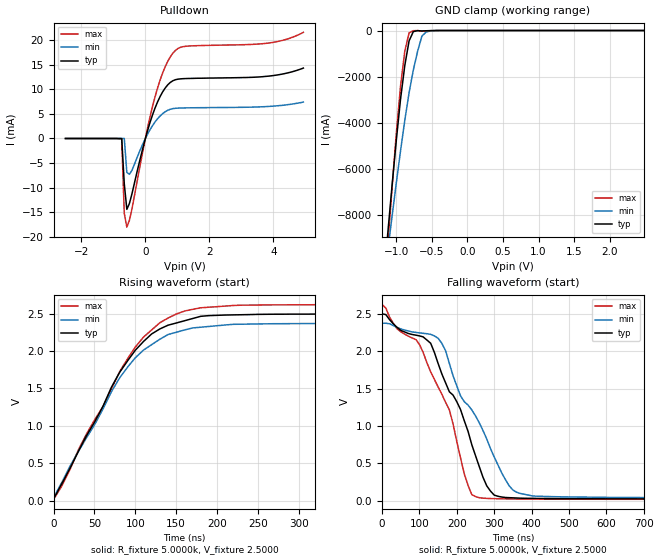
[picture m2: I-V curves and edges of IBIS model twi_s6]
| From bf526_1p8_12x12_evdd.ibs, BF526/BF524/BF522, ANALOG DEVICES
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[Model]   twi_s6
Model_type I/O_open_drain
Polarity   Non-Inverting
Enable   Active-Low
Vinl =   0.7500V
Vinh =   1.7500V
Vmeas =  1.2500V
Cref =   50.0000pF
Rref =   5.0000k
Vref =   2.5000V
C_comp   7.1300pF   6.4200pF   7.8500pF
[Temperature Range]   25.0000   0.1250k   0.0
[Voltage Range]   2.5000V   2.3750V   2.6250V
[Pullup Reference]   2.5000V   2.3750V   2.6250V
[Pulldown Reference]   0.0V   0.0V   0.0V
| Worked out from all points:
|   slope of the pulldown table from 0 to 0.375 V, typ, clamps not added: 50.9 ohm
|   GND clamp passes 1 mA (typ) near -0.43 V on its own axis
|   rising waveform, R_fixture 5.0000k, V_fixture 2.5000: 20-80 % time 75.4ns typ, 77.3ns min, 78.7ns max; typ from 0.021 V to 2.5 V
|   falling waveform, R_fixture 5.0000k, V_fixture 2.5000: 20-80 % time 117ns typ, 132ns min, 113ns max; typ from 2.5 V to 0.021 V
[Pulldown]
|Voltage   I(typ)   I(min)   I(max)
-2.5V     0A         0A         0A
-740mV    -20uA      0A         -54uA
-660mV    -9.21mA    0A         -15.24mA
-580mV    -14.43mA   -6.9mA     -18.05mA
-420mV    -11.27mA   -6.485mA   -14.35mA
-20mV     -489.5uA   -271.8uA   -650.4uA
300mV     6.168mA    3.352mA    8.441mA
620mV     10.28mA    5.448mA    14.63mA
860mV     11.76mA    6.085mA    17.38mA
1.26V     12.2mA     6.231mA    18.77mA
3.98V     12.8mA     6.579mA    19.56mA
4.94V     14.34mA    7.417mA    21.62mA
[GND_clamp]
|Voltage   I(typ)   I(min)   I(max)
-2.5V     -59.97A    -45.67A    -72.09A
-1.12V    -8.799A    -9.55A     -9.344A
-1.06V    -6.738A    -8.066A    -6.84A
-1V       -4.765A    -6.614A    -4.473A
-940mV    -2.967A    -5.209A    -2.401A
-880mV    -1.51A     -3.883A    -890.2mA
-820mV    -448.1mA   -2.694A    -100.8mA
-760mV    -46.3mA    -1.705A    -8.654mA
-700mV    -4.927mA   -897.9mA   -1.463mA
-640mV    -19.29mA   -242.9mA   -27.34mA
-580mV    -10.88mA   -64.03mA   -16.8mA
2.48V     785pA      18.81nA    1.1nA
[Ramp]
| variable   typ   min   max
dV/dt_r  1.4870/75.6132n   1.4031/77.4408n   1.5647/78.9275n
dV/dt_f  1.4874/0.1174u   1.4024/0.1316u   1.5652/0.1136u
R_load = 5.0000k
[Rising Waveform]
R_fixture= 5.0000k
V_fixture= 2.5000
V_fixture_min= 2.3750
V_fixture_max= 2.6250
L_fixture= 0.0H
C_fixture= 0.0F
|time   V(typ)   V(min)   V(max)
0s        20.6mV     35.47mV    16.21mV
60.61ns   1.265V     1.228V     1.26V
70.71ns   1.515V     1.455V     1.494V
80.81ns   1.715V     1.642V     1.725V
100ns     2.012V     1.911V     2.054V
130ns     2.297V     2.159V     2.38V
160ns     2.406V     2.283V     2.536V
180ns     2.466V     2.32V      2.58V
250ns     2.492V     2.364V     2.617V
1us       2.499V     2.374V     2.624V
[Falling Waveform]
R_fixture= 5.0000k
V_fixture= 2.5000
V_fixture_min= 2.3750
V_fixture_max= 2.6250
L_fixture= 0.0H
C_fixture= 0.0F
|time   V(typ)   V(min)   V(max)
0s        2.5V       2.374V     2.625V
100ns     2.205V     2.245V     2.09V
130ns     2.106V     2.225V     1.724V
160ns     1.694V     2.104V     1.422V
180ns     1.456V     1.835V     1.214V
220ns     1.067V     1.323V     354.6mV
250ns     600.1mV    1.133V     53.11mV
300ns     72.67mV    582.5mV    25.56mV
370ns     31.89mV    94.62mV    20.48mV
1us       20.94mV    36.59mV    16.31mV
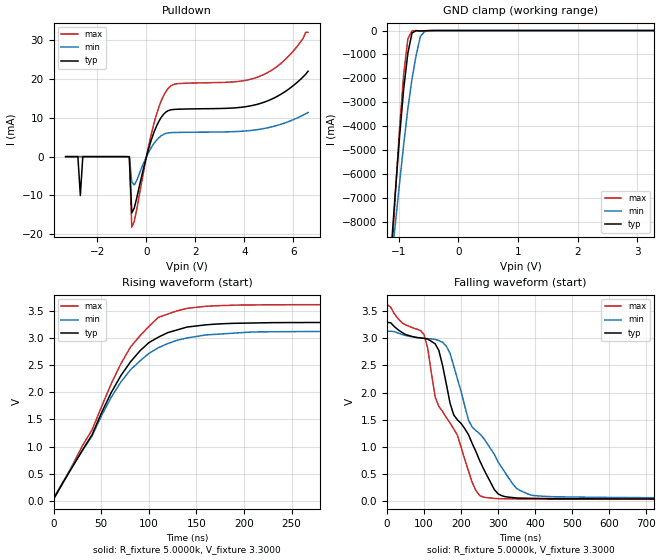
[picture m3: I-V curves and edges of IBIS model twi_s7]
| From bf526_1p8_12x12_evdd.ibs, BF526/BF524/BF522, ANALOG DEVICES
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[Model]   twi_s7
Model_type I/O_open_drain
Polarity   Non-Inverting
Enable   Active-Low
Vinl =   0.9900V
Vinh =   2.3100V
Vmeas =  1.6500V
Cref =   50.0000pF
Rref =   5.0000k
Vref =   3.3000V
C_comp   7.1300pF   6.4200pF   7.8500pF
[Temperature Range]   25.0000   0.1250k   0.0
[Voltage Range]   3.3000V   3.1350V   3.6300V
[Pullup Reference]   3.3000V   3.1350V   3.6300V
[Pulldown Reference]   0.0V   0.0V   0.0V
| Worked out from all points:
|   slope of the pulldown table from 0 to 0.495 V, typ, clamps not added: 55.2 ohm
|   GND clamp passes 1 mA (typ) near -0.44 V on its own axis
|   rising waveform, R_fixture 5.0000k, V_fixture 3.3000: 20-80 % time 62.7ns typ, 66ns min, 61.5ns max; typ from 0.027 V to 3.3 V
|   falling waveform, R_fixture 5.0000k, V_fixture 3.3000: 20-80 % time 109ns typ, 126ns min, 104ns max; typ from 3.3 V to 0.028 V
[Pulldown]
|Voltage   I(typ)   I(min)   I(max)
-3.3V     0A         0A         0A
-2.8V     0A         0A         0A
-2.7V     -10mA      0A         0A
-2.6V     0A         0A         0A
-700mV    -34uA      0A         -69uA
-600mV    -14.49mA   -6.5mA     -18.15mA
-500mV    -13.25mA   -7.29mA    -16.66mA
300mV     6.168mA    3.352mA    8.441mA
900mV     11.88mA    6.125mA    17.68mA
4.6V      13.61mA    7.021mA    20.62mA
5.6V      16.49mA    8.563mA    24.62mA
6.6V      22mA       11.38mA    32mA
[GND_clamp]
|Voltage   I(typ)   I(min)   I(max)
-3.3V     -90.22A    -67.03A    -109.2A
-1.13V    -9.148A    -9.799A    -9.77A
-1.06V    -6.738A    -8.066A    -6.84A
-990mV    -4.45A     -6.376A    -4.1A
-920mV    -2.435A    -4.756A    -1.824A
-850mV    -941.8mA   -3.266A    -348.1mA
-780mV    -99.67mA   -2.011A    -19.24mA
-710mV    -7.041mA   -1.022A    -1.727mA
-640mV    -19.29mA   -242.9mA   -27.34mA
-570mV    -9.687mA   -51.15mA   -15.19mA
-500mV    -3.403mA   -11.15mA   -6.097mA
3.28V     11.02nA    63.01nA    22.06nA
[Ramp]
| variable   typ   min   max
dV/dt_r  1.9630/62.0862n   1.8515/65.3191n   2.1633/60.9264n
dV/dt_f  1.9627/0.1093u   1.8507/0.1256u   2.1639/0.1044u
R_load = 5.0000k
[Rising Waveform]
R_fixture= 5.0000k
V_fixture= 3.3000
V_fixture_min= 3.1350
V_fixture_max= 3.6300
L_fixture= 0.0H
C_fixture= 0.0F
|time   V(typ)   V(min)   V(max)
0s        27.28mV    47.13mV    22.48mV
40.4ns    1.216V     1.194V     1.307V
60.61ns   1.999V     1.912V     2.163V
80.81ns   2.567V     2.42V      2.841V
100ns     2.921V     2.721V     3.221V
110ns     3.023V     2.827V     3.39V
140ns     3.21V      3.008V     3.556V
160ns     3.252V     3.065V     3.595V
240ns     3.293V     3.125V     3.623V
1us       3.299V     3.133V     3.628V
[Falling Waveform]
R_fixture= 5.0000k
V_fixture= 3.3000
V_fixture_min= 3.1350
V_fixture_max= 3.6300
L_fixture= 0.0H
C_fixture= 0.0F
|time   V(typ)   V(min)   V(max)
0s        3.299V     3.134V     3.629V
100ns     3.002V     3.003V     3.072V
130ns     2.901V     2.983V     1.917V
160ns     2.16V      2.857V     1.536V
180ns     1.586V     2.491V     1.324V
220ns     1.219V     1.486V     543.5mV
250ns     739.8mV    1.239V     92.98mV
300ns     122.8mV    714mV      34.68mV
390ns     40.78mV    97.82mV    27.47mV
1us       27.9mV     48.98mV    22.48mV
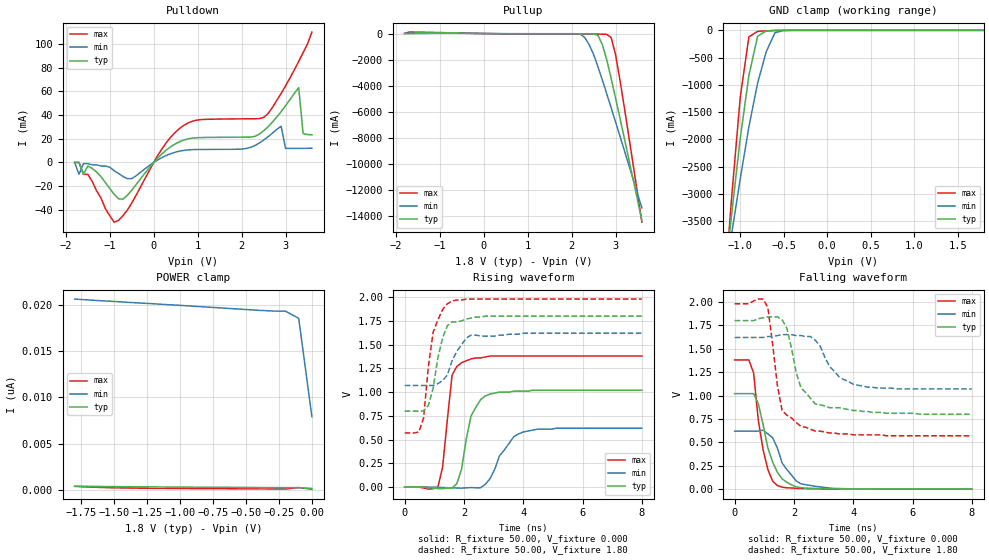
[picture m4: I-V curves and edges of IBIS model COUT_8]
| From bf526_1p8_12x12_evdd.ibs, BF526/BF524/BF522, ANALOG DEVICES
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|   Model prw0408swcdg_25
[Model]   COUT_8
Model_type   I/O
Polarity   Non-Inverting
Enable   Active-Low
Vinl =   0.70V
Vinh =   1.00V
Vmeas =   1.20V
Cref =  50.00pF
Rref =   1.00M
Vref =  0.000V
C_comp   4.81pF   4.33pF   5.29pF
[Temperature Range]   25.00   0.12k   -40.00
[Voltage Range]   1.80V   1.62V   1.98V
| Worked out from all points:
|   slope of the pulldown table from 0 to 0.27 V, typ, clamps not added: 27.1 ohm
|   slope of the pullup table from 0 to 0.27 V, typ, clamps not added: 26.9 ohm
|   GND clamp passes 1 mA (typ) near -0.53 V on its own axis
|   rising waveform, R_fixture 50.00, V_fixture 0.000: 20-80 % time 430ps typ, 666ps min, 273ps max; typ from 0 V to 1.02 V
|   rising waveform, R_fixture 50.00, V_fixture 1.80: 20-80 % time 392ps typ, 503ps min, 368ps max; typ from 0.8 V to 1.8 V
|   falling waveform, R_fixture 50.00, V_fixture 0.000: 20-80 % time 537ps typ, 626ps min, 387ps max; typ from 1.02 V to 0 V
|   falling waveform, R_fixture 50.00, V_fixture 1.80: 20-80 % time 633ps typ, 720ps min, 374ps max; typ from 1.8 V to 0.8 V
[Pulldown]
| voltage   I(typ)   I(min)   I(max)
-1.8V     0A         0A         0A
-1.7V     0A         -10mA      0A
-1.6V     -10mA      -1mA       -10mA
-1.4V     -5mA       -2mA       -16mA
-800mV    -30.7mA    -9.3mA     -48.85mA
500mV     15.88mA    8.74mA     25.76mA
2.5V      26.66mA    18.81mA    37.95mA
2.9V      42.91mA    30.55mA    58.28mA
3V        47.85mA    11.93mA    64.57mA
3.3V      63.16mA    11.88mA    85.3mA
3.4V      24.4mA     11.91mA    92.63mA
3.6V      23.31mA    12mA       110mA
[Pullup]
| voltage   I(typ)   I(min)   I(max)
-1.8V     1.48mA     550uA      10.03mA
-1.6V     2.84mA     560uA      110mA
2.2V      -22.71mA   -39.81mA   -37.75mA
2.3V      -23.18mA   -310mA     -37.82mA
2.4V      -25.42mA   -850mA     -37.94mA
2.6V      -130mA     -2.54A     -42.67mA
2.7V      -850mA     -3.56A     -49.75mA
2.8V      -2.01A     -4.61A     -61.08mA
2.9V      -3.43A     -5.68A     -310mA
3V        -4.93A     -6.76A     -1.61A
3.1V      -6.46A     -7.85A     -3.55A
3.6V      -14.31A    -13.35A    -14.44A
[GND_clamp]
| voltage   I(typ)   I(min)   I(max)
-1.8V     -14.28A    -11.35A    -18.41A
-1.2V     -4.9A      -4.81A     -5.19A
-1.1V     -3.4A      -3.75A     -3.1A
-1V       -1.99A     -2.73A     -1.24A
-900mV    -830mA     -1.77A     -120mA
-800mV    -110mA     -970mA     -19.21mA
-700mV    -9.89mA    -390mA     -9.78mA
-600mV    -2.57mA    -42.87mA   -3.5mA
-500mV    -460uA     -4.38mA    -550uA
1.8V      170pA      19.28nA    82.46pA
[POWER_clamp]
| voltage   I(typ)   I(min)   I(max)
-1.8V     420pA      20.63nA    400pA
-1.5V     370pA      20.37nA    240pA
-1.3V     350pA      20.2nA     200pA
-400mV    270pA      19.41nA    130pA
-200mV    260pA      19.32nA    110pA
-100mV    260pA      18.55nA    270pA
0V        170pA      7.92nA     95.65pA
[Ramp]
| variable   typ   min   max
dV/dt_r   0.61/0.48n   0.37/0.67n   0.83/0.28n
dV/dt_f   0.60/0.65n   0.33/0.73n   0.84/0.37n
R_load = 50.00
[Rising Waveform]
R_fixture = 50.00
V_fixture = 0.000
V_fixture_min = 0.000
V_fixture_max = 0.000
L_fixture = 0.000H
C_fixture = 0.000F
| time   V(typ)   V(min)   V(max)
0s        0V         0V         0V
1.12ns    -15.49mV   -2.64mV    -1.94mV
1.28ns    -16.64mV   -4.27mV    210mV
1.6ns     -11.55mV   -8.42mV    1.18V
1.92ns    190mV      -10.99mV   1.31V
2.24ns    750mV      -5.47mV    1.35V
2.72ns    960mV      29.12mV    1.37V
3.2ns     1V         330mV      1.38V
4ns       1.01V      580mV      1.38V
8ns       1.02V      620mV      1.38V
[Rising Waveform]
R_fixture = 50.00
V_fixture = 1.80
V_fixture_min = 1.62
V_fixture_max = 1.98
L_fixture = 0.000H
C_fixture = 0.000F
| time   V(typ)   V(min)   V(max)
0s        800mV      1.07V      570mV
480ps     800mV      1.07V      580mV
640ps     800mV      1.07V      730mV
800ps     860mV      1.07V      1.27V
960ps     1.04V      1.07V      1.63V
1.12ns    1.36V      1.09V      1.76V
1.28ns    1.57V      1.12V      1.87V
1.6ns     1.74V      1.33V      1.96V
2.24ns    1.78V      1.6V       1.98V
8ns       1.8V       1.62V      1.98V
[Falling Waveform]
R_fixture = 50.00
V_fixture = 0.000
V_fixture_min = 0.000
V_fixture_max = 0.000
L_fixture = 0.000H
C_fixture = 0.000F
| time   V(typ)   V(min)   V(max)
0s        1.02V      620mV      1.38V
480ps     1.02V      620mV      1.38V
640ps     1.02V      620mV      1.24V
800ps     910mV      620mV      730mV
960ps     690mV      630mV      420mV
1.12ns    440mV      590mV      210mV
1.44ns    180mV      440mV      38.63mV
1.6ns     110mV      280mV      21.04mV
2.24ns    15.2mV     56.58mV    6.95mV
8ns       40.15uV    66.62uV    5.02uV
[Falling Waveform]
R_fixture = 50.00
V_fixture = 1.80
V_fixture_min = 1.62
V_fixture_max = 1.98
L_fixture = 0.000H
C_fixture = 0.000F
| time   V(typ)   V(min)   V(max)
0s        1.8V       1.62V      1.98V
1.12ns    1.84V      1.63V      1.94V
1.44ns    1.84V      1.64V      1.11V
1.6ns     1.81V      1.65V      840mV
1.76ns    1.72V      1.65V      790mV
2.24ns    1.08V      1.64V      670mV
2.72ns    910mV      1.59V      620mV
3.2ns     870mV      1.31V      600mV
4ns       840mV      1.12V      580mV
8ns       800mV      1.07V      570mV
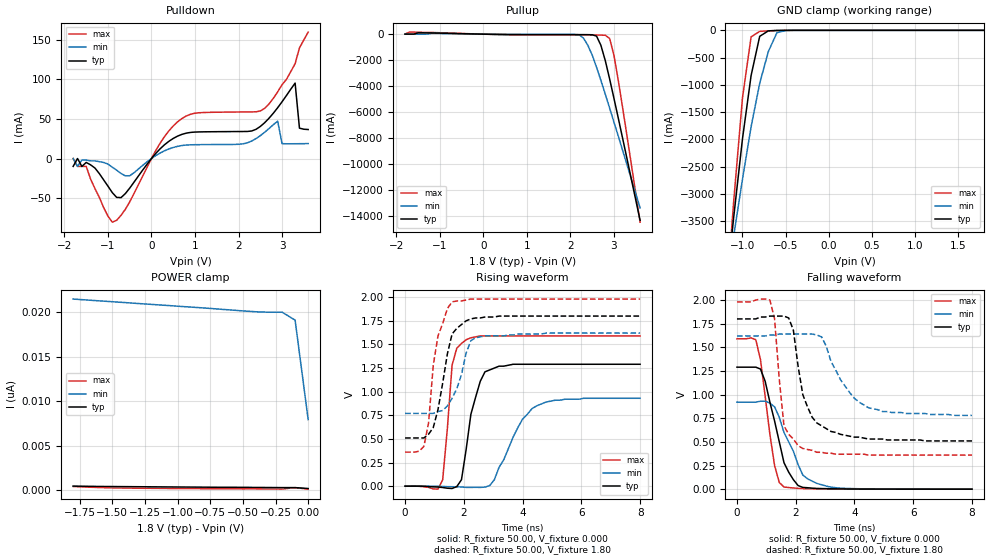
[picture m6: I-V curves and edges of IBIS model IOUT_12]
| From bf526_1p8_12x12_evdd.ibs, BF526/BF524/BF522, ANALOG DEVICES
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|   Model prw0812swcdg_25
[Model]   IOUT_12
Model_type   I/O
Polarity   Non-Inverting
Enable   Active-Low
Vinl =   0.70V
Vinh =   1.00V
Vmeas =   1.20V
Cref =  50.00pF
Rref =   1.00M
Vref =  0.000V
C_comp   4.56pF   4.10pF   5.01pF
[Temperature Range]   25.00   0.12k   -40.00
[Voltage Range]   1.80V   1.62V   1.98V
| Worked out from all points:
|   slope of the pulldown table from 0 to 0.27 V, typ, clamps not added: 17 ohm
|   slope of the pullup table from 0 to 0.27 V, typ, clamps not added: 16.9 ohm
|   GND clamp passes 1 mA (typ) near -0.53 V on its own axis
|   rising waveform, R_fixture 50.00, V_fixture 0.000: 20-80 % time 472ps typ, 926ps min, 244ps max; typ from 0 V to 1.29 V
|   rising waveform, R_fixture 50.00, V_fixture 1.80: 20-80 % time 464ps typ, 513ps min, 398ps max; typ from 0.51 V to 1.8 V
|   falling waveform, R_fixture 50.00, V_fixture 0.000: 20-80 % time 597ps typ, 726ps min, 407ps max; typ from 1.29 V to 0 V
|   falling waveform, R_fixture 50.00, V_fixture 1.80: 20-80 % time 570ps typ, 950ps min, 279ps max; typ from 1.8 V to 0.51 V
[Pulldown]
| voltage   I(typ)   I(min)   I(max)
-1.8V     -10mA      0A         0A
-1.4V     -8mA       -3mA       -26mA
-1V       -35mA      -7mA       -73mA
-800mV    -49.2mA    -14.8mA    -78.15mA
-500mV    -37.44mA   -21.82mA   -54.81mA
600mV     28.34mA    15.42mA    46.41mA
2.5V      40.54mA    28.91mA    60.13mA
2.9V      64.32mA    47.23mA    84.42mA
3V        71.8mA     18.76mA    93.51mA
3.3V      95.44mA    18.69mA    120mA
3.4V      38.41mA    18.74mA    140mA
3.6V      36.68mA    18.88mA    160mA
[Pullup]
| voltage   I(typ)   I(min)   I(max)
-1.8V     1.75mA     550uA      14.91mA
-1.6V     3.92mA     570uA      160mA
2.2V      -36.14mA   -47.43mA   -60.12mA
2.3V      -36.65mA   -310mA     -60.23mA
2.4V      -38.95mA   -860mA     -60.39mA
2.6V      -150mA     -2.55A     -65.28mA
2.7V      -860mA     -3.56A     -72.49mA
2.8V      -2.03A     -4.61A     -83.96mA
2.9V      -3.44A     -5.68A     -330mA
3V        -4.94A     -6.77A     -1.64A
3.1V      -6.47A     -7.85A     -3.57A
3.6V      -14.32A    -13.36A    -14.46A
[GND_clamp]
| voltage   I(typ)   I(min)   I(max)
-1.8V     -14.28A    -11.35A    -18.41A
-1.2V     -4.9A      -4.81A     -5.19A
-1.1V     -3.4A      -3.75A     -3.1A
-1V       -1.99A     -2.73A     -1.24A
-900mV    -830mA     -1.77A     -120mA
-800mV    -110mA     -970mA     -19.21mA
-700mV    -9.89mA    -390mA     -9.78mA
-600mV    -2.57mA    -42.87mA   -3.5mA
-500mV    -460uA     -4.38mA    -550uA
1.8V      170pA      19.94nA    82.46pA
[POWER_clamp]
| voltage   I(typ)   I(min)   I(max)
-1.8V     440pA      21.46nA    400pA
-1.3V     370pA      20.96nA    200pA
-400mV    290pA      20.03nA    130pA
-200mV    270pA      19.99nA    110pA
-100mV    270pA      19.09nA    270pA
0V        170pA      7.92nA     95.65pA
[Ramp]
| variable   typ   min   max
dV/dt_r   0.78/0.46n   0.56/0.89n   0.96/0.27n
dV/dt_f   0.77/0.58n   0.50/0.96n   0.97/0.31n
R_load = 50.00
[Rising Waveform]
R_fixture = 50.00
V_fixture = 0.000
V_fixture_min = 0.000
V_fixture_max = 0.000
L_fixture = 0.000H
C_fixture = 0.000F
| time   V(typ)   V(min)   V(max)
0s        0V         0V         0V
1.28ns    -14.22mV   -3.55mV    67.64mV
1.6ns     -24.61mV   -6.05mV    1.28V
1.92ns    68.25mV    -8.49mV    1.51V
2.08ns    390mV      -13.13mV   1.55V
2.24ns    760mV      -13.22mV   1.57V
2.72ns    1.21V      -9.73mV    1.59V
4ns       1.29V      710mV      1.59V
4.48ns    1.29V      850mV      1.59V
8ns       1.29V      930mV      1.59V
[Rising Waveform]
R_fixture = 50.00
V_fixture = 1.80
V_fixture_min = 1.62
V_fixture_max = 1.98
L_fixture = 0.000H
C_fixture = 0.000F
| time   V(typ)   V(min)   V(max)
0s        510mV      770mV      360mV
640ps     510mV      770mV      420mV
800ps     550mV      770mV      670mV
960ps     620mV      770mV      1.28V
1.12ns    810mV      790mV      1.59V
1.44ns    1.4V       850mV      1.88V
1.6ns     1.61V      930mV      1.95V
2.24ns    1.77V      1.54V      1.98V
2.4ns     1.78V      1.57V      1.98V
8ns       1.8V       1.62V      1.98V
[Falling Waveform]
R_fixture = 50.00
V_fixture = 0.000
V_fixture_min = 0.000
V_fixture_max = 0.000
L_fixture = 0.000H
C_fixture = 0.000F
| time   V(typ)   V(min)   V(max)
0s        1.29V      920mV      1.59V
640ps     1.29V      920mV      1.58V
800ps     1.27V      930mV      1.37V
960ps     1.14V      930mV      980mV
1.28ns    720mV      870mV      250mV
1.44ns    500mV      760mV      70.38mV
1.6ns     280mV      600mV      22.75mV
2.24ns    18.52mV    150mV      6.49mV
2.72ns    7.5mV      60.55mV    3.02mV
8ns       42.66uV    87.17uV    12.15uV
[Falling Waveform]
R_fixture = 50.00
V_fixture = 1.80
V_fixture_min = 1.62
V_fixture_max = 1.98
L_fixture = 0.000H
C_fixture = 0.000F
| time   V(typ)   V(min)   V(max)
0s        1.8V       1.62V      1.98V
1.12ns    1.83V      1.63V      2V
1.28ns    1.83V      1.63V      1.8V
1.6ns     1.83V      1.64V      670mV
1.92ns    1.68V      1.64V      530mV
2.08ns    1.3V       1.64V      460mV
2.56ns    760mV      1.64V      410mV
3.2ns     610mV      1.35V      380mV
4.48ns    530mV      860mV      360mV
8ns       510mV      780mV      360mV
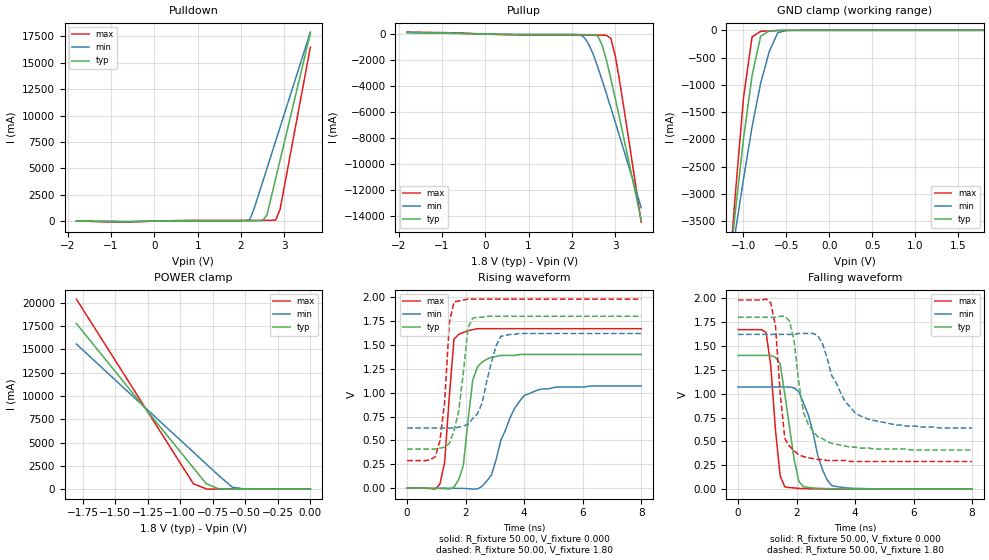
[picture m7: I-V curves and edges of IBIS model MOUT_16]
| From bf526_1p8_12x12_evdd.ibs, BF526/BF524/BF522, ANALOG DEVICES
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|   Model prw1216cdg_25
[Model]   MOUT_16
Model_type   I/O
Polarity   Non-Inverting
Enable   Active-Low
Vinl =   0.70V
Vinh =   1.00V
Vmeas =   1.20V
Cref =  50.00pF
Rref =   1.00M
Vref =  0.000V
C_comp   4.80pF   4.32pF   5.28pF
[Temperature Range]   25.00   0.12k   -40.00
[Voltage Range]   1.80V   1.62V   1.98V
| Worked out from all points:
|   slope of the pulldown table from 0 to 0.27 V, typ, clamps not added: 13.6 ohm
|   slope of the pullup table from 0 to 0.27 V, typ, clamps not added: 13.3 ohm
|   GND clamp passes 1 mA (typ) near -0.53 V on its own axis
|   POWER clamp passes 1 mA (typ) near -0.53 V on its own axis
|   rising waveform, R_fixture 50.00, V_fixture 0.000: 20-80 % time 303ps typ, 763ps min, 245ps max; typ from 0 V to 1.4 V
|   rising waveform, R_fixture 50.00, V_fixture 1.80: 20-80 % time 359ps typ, 506ps min, 252ps max; typ from 0.41 V to 1.8 V
|   falling waveform, R_fixture 50.00, V_fixture 0.000: 20-80 % time 406ps typ, 577ps min, 276ps max; typ from 1.4 V to 0 V
|   falling waveform, R_fixture 50.00, V_fixture 1.80: 20-80 % time 459ps typ, 911ps min, 272ps max; typ from 1.8 V to 0.41 V
[Pulldown]
| voltage   I(typ)   I(min)   I(max)
-1.8V     -10mA      0A         -10mA
-900mV    -54mA      -13mA      -100mA
600mV     35.42mA    19.27mA    58.01mA
2.1V      42.7mA     29mA       73.65mA
2.2V      42.77mA    140mA      73.7mA
2.3V      43.22mA    1.16A      73.75mA
2.5V      59.87mA    3.73A      74.66mA
2.6V      610mA      5.02A      77.37mA
2.8V      4.04A      7.6A       99.23mA
2.9V      5.76A      8.88A      1.1A
3.6V      17.81A     17.91A     16.5A
[Pullup]
| voltage   I(typ)   I(min)   I(max)
-1.8V     130mA      100mA      150mA
2.2V      -46.27mA   -53.72mA   -75.17mA
2.3V      -46.79mA   -320mA     -75.36mA
2.4V      -49mA      -860mA     -75.6mA
2.5V      -56.4mA    -1.62A     -76.56mA
2.6V      -160mA     -2.56A     -80.35mA
2.7V      -870mA     -3.57A     -87.33mA
2.8V      -2.04A     -4.62A     -98.53mA
2.9V      -3.45A     -5.69A     -350mA
3V        -4.95A     -6.77A     -1.65A
3.1V      -6.48A     -7.86A     -3.58A
3.6V      -14.33A    -13.37A    -14.48A
[GND_clamp]
| voltage   I(typ)   I(min)   I(max)
-1.8V     -14.28A    -11.35A    -18.41A
-1.2V     -4.9A      -4.81A     -5.19A
-1.1V     -3.4A      -3.75A     -3.1A
-1V       -1.99A     -2.73A     -1.24A
-900mV    -830mA     -1.77A     -120mA
-800mV    -110mA     -970mA     -19.15mA
-700mV    -9.85mA    -390mA     -9.73mA
-600mV    -2.55mA    -42.82mA   -3.48mA
-500mV    -450uA     -4.35mA    -550uA
1.8V      150pA      1.58uA     73.18pA
[POWER_clamp]
| voltage   I(typ)   I(min)   I(max)
-1.8V     17.76A     15.56A     20.38A
-900mV    2.28A      3.97A      590mA
-800mV    570mA      2.68A      16.99mA
-700mV    17.03mA    1.4A       7.08mA
-600mV    2.36mA     210mA      2.77mA
-500mV    460uA      11.86mA    530uA
0V        150pA      7.78nA     85.42pA
[Ramp]
| variable   typ   min   max
dV/dt_r   0.84/0.37n   0.64/0.76n   1.00/0.21n
dV/dt_f   0.83/0.50n   0.59/0.93n   1.01/0.27n
R_load = 50.00
[Rising Waveform]
R_fixture = 50.00
V_fixture = 0.000
V_fixture_min = 0.000
V_fixture_max = 0.000
L_fixture = 0.000H
C_fixture = 0.000F
| time   V(typ)   V(min)   V(max)
0s        0V         0V         0V
1.12ns    -1.58mV    5.35uV     45.36mV
1.28ns    -3.19mV    -55.94uV   270mV
1.6ns     11.68mV    -630uV     1.56V
1.76ns    89.29mV    -1.03mV    1.61V
1.92ns    240mV      -1.65mV    1.63V
2.24ns    1.13V      -7.76mV    1.66V
2.56ns    1.32V      20.95mV    1.67V
4ns       1.4V       970mV      1.67V
8ns       1.4V       1.07V      1.67V
[Rising Waveform]
R_fixture = 50.00
V_fixture = 1.80
V_fixture_min = 1.62
V_fixture_max = 1.98
L_fixture = 0.000H
C_fixture = 0.000F
| time   V(typ)   V(min)   V(max)
0s        410mV      630mV      290mV
960ps     410mV      630mV      330mV
1.28ns    430mV      630mV      900mV
1.44ns    470mV      630mV      1.73V
1.6ns     600mV      630mV      1.95V
1.76ns    810mV      640mV      1.96V
2.08ns    1.68V      670mV      1.98V
2.24ns    1.78V      730mV      1.98V
3.2ns     1.8V       1.59V      1.98V
8ns       1.8V       1.62V      1.98V
[Falling Waveform]
R_fixture = 50.00
V_fixture = 0.000
V_fixture_min = 0.000
V_fixture_max = 0.000
L_fixture = 0.000H
C_fixture = 0.000F
| time   V(typ)   V(min)   V(max)
0s        1.4V       1.07V      1.67V
960ps     1.4V       1.07V      1.64V
1.12ns    1.4V       1.07V      1.29V
1.44ns    1.31V      1.07V      140mV
1.6ns     990mV      1.07V      24.09mV
1.92ns    310mV      1.06V      12.54mV
2.24ns    24.77mV    900mV      5.92mV
2.88ns    7.54mV     210mV      2.28mV
3.2ns     4.54mV     38.64mV    1.34mV
8ns       45.31uV    150uV      3.74uV
[Falling Waveform]
R_fixture = 50.00
V_fixture = 1.80
V_fixture_min = 1.62
V_fixture_max = 1.98
L_fixture = 0.000H
C_fixture = 0.000F
| time   V(typ)   V(min)   V(max)
0s        1.8V       1.62V      1.98V
1.12ns    1.8V       1.62V      1.95V
1.28ns    1.8V       1.62V      1.71V
1.6ns     1.81V      1.62V      530mV
1.92ns    1.55V      1.62V      400mV
2.08ns    1.11V      1.63V      360mV
2.24ns    800mV      1.63V      340mV
2.72ns    550mV      1.61V      310mV
4.16ns    430mV      770mV      290mV
8ns       410mV      640mV      290mV
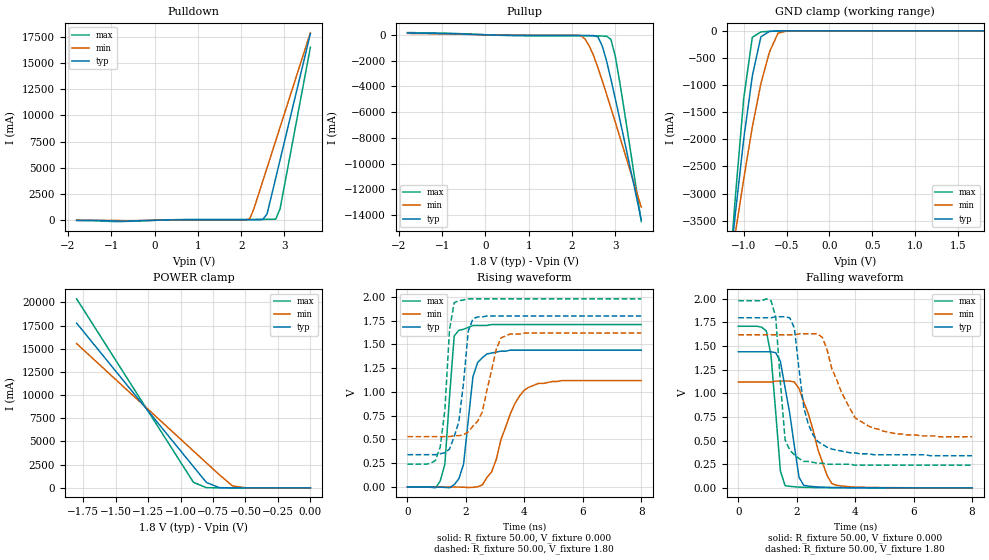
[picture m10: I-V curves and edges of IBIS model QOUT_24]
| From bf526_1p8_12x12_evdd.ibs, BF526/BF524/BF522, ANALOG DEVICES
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|   Model prw1624cdg_25
[Model]   QOUT_24
Model_type   I/O
Polarity   Non-Inverting
Enable   Active-Low
Vinl =   0.70V
Vinh =   1.00V
Vmeas =   1.20V
Cref =  50.00pF
Rref =   1.00M
Vref =  0.000V
C_comp   4.64pF   4.17pF   5.10pF
[Temperature Range]   25.00   0.12k   -40.00
[Voltage Range]   1.80V   1.62V   1.98V
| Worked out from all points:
|   slope of the pulldown table from 0 to 0.27 V, typ, clamps not added: 11.3 ohm
|   slope of the pullup table from 0 to 0.27 V, typ, clamps not added: 11.8 ohm
|   GND clamp passes 1 mA (typ) near -0.53 V on its own axis
|   POWER clamp passes 1 mA (typ) near -0.53 V on its own axis
|   rising waveform, R_fixture 50.00, V_fixture 0.000: 20-80 % time 301ps typ, 753ps min, 242ps max; typ from 0 V to 1.44 V
|   rising waveform, R_fixture 50.00, V_fixture 1.80: 20-80 % time 339ps typ, 512ps min, 246ps max; typ from 0.34 V to 1.8 V
|   falling waveform, R_fixture 50.00, V_fixture 0.000: 20-80 % time 446ps typ, 675ps min, 270ps max; typ from 1.44 V to 0 V
|   falling waveform, R_fixture 50.00, V_fixture 1.80: 20-80 % time 469ps typ, 887ps min, 258ps max; typ from 1.8 V to 0.34 V
[Pulldown]
| voltage   I(typ)   I(min)   I(max)
-1.8V     -10mA      0A         -10mA
-800mV    -73.8mA    -22.2mA    -120mA
600mV     42.5mA     23.13mA    69.61mA
2.1V      51.24mA    33.46mA    88.37mA
2.2V      51.32mA    140mA      88.44mA
2.3V      51.78mA    1.16A      88.5mA
2.5V      68.44mA    3.74A      89.43mA
2.6V      620mA      5.02A      92.15mA
2.8V      4.05A      7.6A       110mA
2.9V      5.77A      8.89A      1.11A
3.6V      17.82A     17.91A     16.51A
[Pullup]
| voltage   I(typ)   I(min)   I(max)
-1.8V     140mA      110mA      170mA
2.2V      -52.05mA   -57.07mA   -84.56mA
2.3V      -52.58mA   -320mA     -84.78mA
2.4V      -54.8mA    -870mA     -85.04mA
2.5V      -62.22mA   -1.62A     -86.03mA
2.6V      -160mA     -2.56A     -89.83mA
2.7V      -880mA     -3.57A     -96.83mA
2.8V      -2.04A     -4.62A     -110mA
2.9V      -3.46A     -5.69A     -360mA
3V        -4.95A     -6.77A     -1.66A
3.1V      -6.49A     -7.86A     -3.59A
3.6V      -14.34A    -13.37A    -14.49A
[GND_clamp]
| voltage   I(typ)   I(min)   I(max)
-1.8V     -14.28A    -11.35A    -18.41A
-1.2V     -4.9A      -4.81A     -5.19A
-1.1V     -3.4A      -3.75A     -3.1A
-1V       -1.99A     -2.73A     -1.24A
-900mV    -830mA     -1.77A     -120mA
-800mV    -110mA     -970mA     -19.15mA
-700mV    -9.85mA    -390mA     -9.73mA
-600mV    -2.55mA    -42.82mA   -3.48mA
-500mV    -450uA     -4.35mA    -550uA
1.8V      150pA      1.58uA     73.18pA
[POWER_clamp]
| voltage   I(typ)   I(min)   I(max)
-1.8V     17.76A     15.56A     20.38A
-900mV    2.28A      3.97A      590mA
-800mV    570mA      2.68A      16.99mA
-700mV    17.03mA    1.4A       7.08mA
-600mV    2.36mA     210mA      2.77mA
-500mV    460uA      11.86mA    530uA
0V        150pA      7.78nA     85.42pA
[Ramp]
| variable   typ   min   max
dV/dt_r   0.86/0.36n   0.67/0.73n   1.02/0.21n
dV/dt_f   0.87/0.47n   0.65/0.90n   1.04/0.26n
R_load = 50.00
[Rising Waveform]
R_fixture = 50.00
V_fixture = 0.000
V_fixture_min = 0.000
V_fixture_max = 0.000
L_fixture = 0.000H
C_fixture = 0.000F
| time   V(typ)   V(min)   V(max)
0s        0V         0V         0V
1.12ns    -1.99mV    -6.58uV    61.94mV
1.28ns    -4.34mV    -110uV     240mV
1.6ns     24.57mV    -870uV     1.59V
1.76ns    87.18mV    -1.41mV    1.65V
1.92ns    240mV      -2.37mV    1.66V
2.24ns    1.16V      -4.1mV     1.7V
2.72ns    1.4V       99.96mV    1.7V
4ns       1.44V      1.02V      1.71V
8ns       1.44V      1.12V      1.71V
[Rising Waveform]
R_fixture = 50.00
V_fixture = 1.80
V_fixture_min = 1.62
V_fixture_max = 1.98
L_fixture = 0.000H
C_fixture = 0.000F
| time   V(typ)   V(min)   V(max)
0s        340mV      530mV      240mV
1.12ns    350mV      530mV      420mV
1.28ns    360mV      530mV      810mV
1.44ns    400mV      530mV      1.66V
1.6ns     530mV      540mV      1.94V
1.76ns    690mV      540mV      1.96V
2.08ns    1.64V      580mV      1.98V
2.24ns    1.77V      640mV      1.98V
3.2ns     1.8V       1.57V      1.98V
8ns       1.8V       1.62V      1.98V
[Falling Waveform]
R_fixture = 50.00
V_fixture = 0.000
V_fixture_min = 0.000
V_fixture_max = 0.000
L_fixture = 0.000H
C_fixture = 0.000F
| time   V(typ)   V(min)   V(max)
0s        1.44V      1.12V      1.71V
960ps     1.44V      1.12V      1.66V
1.12ns    1.44V      1.12V      1.4V
1.44ns    1.34V      1.13V      180mV
1.6ns     1.06V      1.13V      22.73mV
2.08ns    110mV      1.05V      7.63mV
2.24ns    26.75mV    910mV      5.53mV
2.72ns    8.81mV     410mV      2.41mV
3.2ns     4.4mV      46.06mV    1.12mV
8ns       30.56uV    120uV      6.83uV
[Falling Waveform]
R_fixture = 50.00
V_fixture = 1.80
V_fixture_min = 1.62
V_fixture_max = 1.98
L_fixture = 0.000H
C_fixture = 0.000F
| time   V(typ)   V(min)   V(max)
0s        1.8V       1.62V      1.98V
1.12ns    1.8V       1.62V      1.98V
1.28ns    1.81V      1.62V      1.81V
1.6ns     1.81V      1.62V      510mV
1.92ns    1.69V      1.62V      350mV
2.08ns    1.25V      1.63V      310mV
2.4ns     670mV      1.63V      280mV
3.04ns    430mV      1.46V      250mV
4.48ns    360mV      650mV      240mV
8ns       340mV      540mV      240mV
